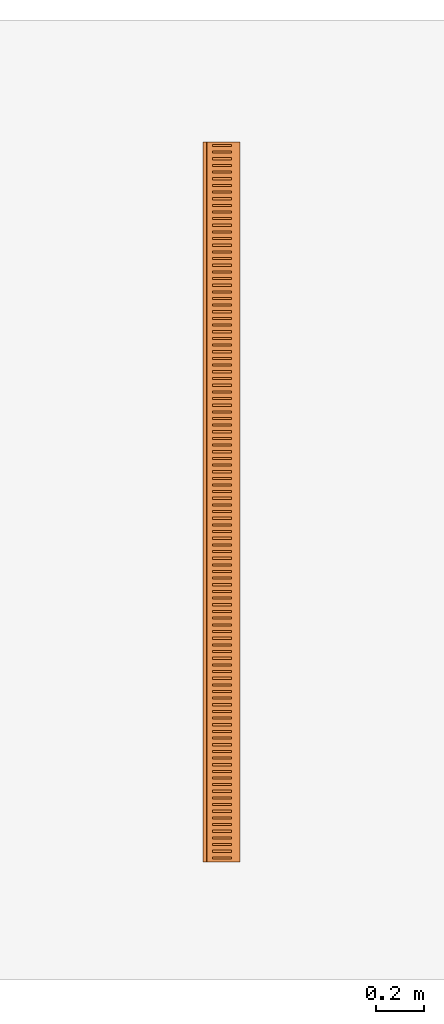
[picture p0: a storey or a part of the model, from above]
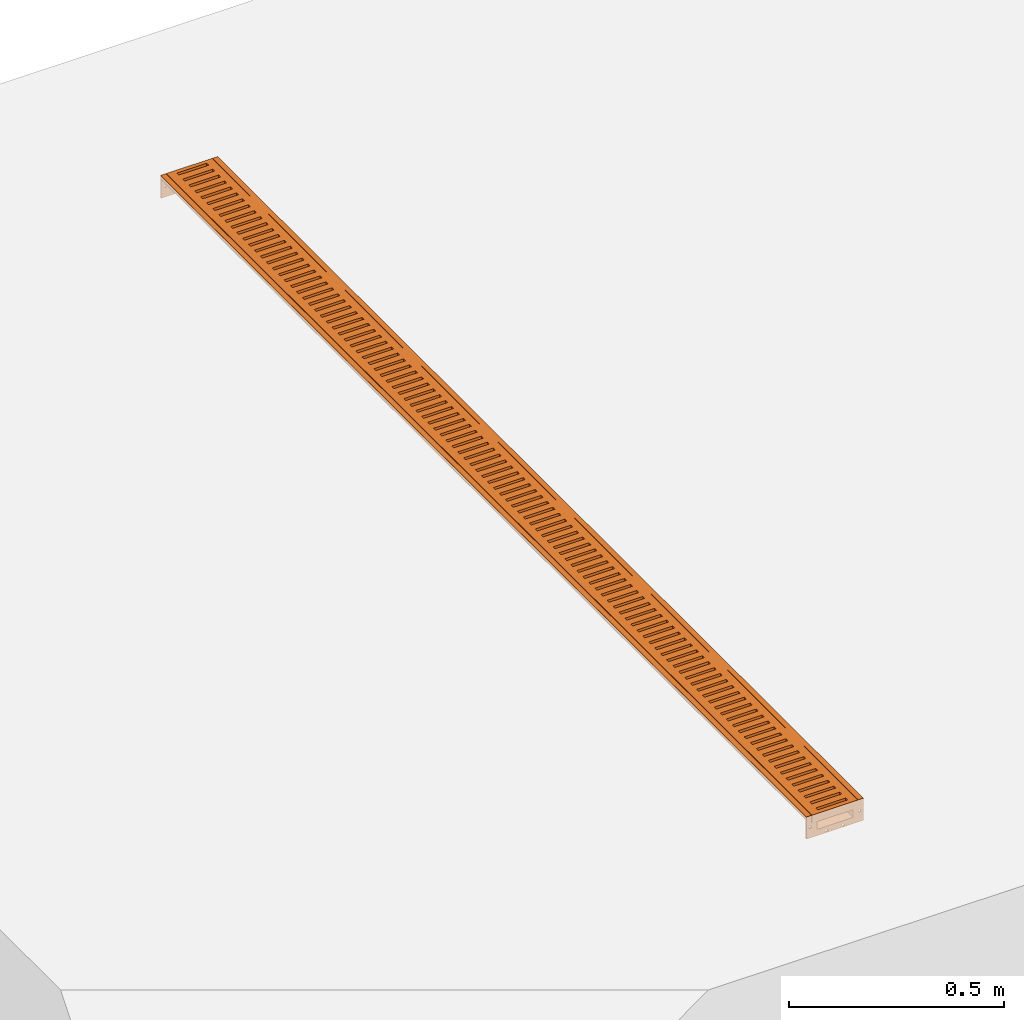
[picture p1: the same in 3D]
Properties of the parts of a building model (IFC2X3)

# File
Description: ViewDefinition [CoordinationView]
File name: 105257 - Level Invert Channel-3000mm LG.ifc
Time: 2014-03-20T14:47:02
Written by: Autodesk Revit 2013
Made in: 20120221_2030(x64)

# IfcProject, Project Number
LongName: Project Name; Phase: Project Status

# IfcSite, Default
RefLatitude: 42, 21, 30, 344238; RefLongitude: -71, -3, -35, -194702; RefElevation: 0 mm

# IfcBuilding
Pset_BuildingCommon - NumberOfStoreys: 1
Other - Project Issue Date: Issue Date; Client Name: Owner; Project Number: Project Number; Project Name: Project Name; Project Status: Project Status; Project Address: ## Street City, State Zip

# IfcBuildingStorey, Level 1
LongName: Level 1; Elevation: 0 mm
Constraints - Elevation Base: 0; Elevation: 0 mm
Graphics - Symbol: M_Level Head - Circle: M_Level Head - Circle; Line Pattern: Center; Color: 0; Symbol at End 1 Default: no; Symbol at End 2 Default: yes; Line Weight: 1
Identity Data - Name: Level 1; Structural: no; Building Story: yes
Dimensions - Computation Height: 0 mm

# IfcBuildingElementProxy: 105257 - Level Invert Channel-3000mm LG, ACO BD Deckline 125 Straight Channel:105257 - Level Invert Channel-3000mm LG:105257 - Level Invert Channel-3000mm LG:225886
In: Level 1
Material: Steel, Galvanized
Construction - 105509 - C250 Perforated Grating - 1000mm Long: no; 15704 - Composite Grating (Black) - 500mm Long: no; 105251 - Endplate - Invert 1: no; 105251 - Endplate - Invert 2: no; 105525 - C250 Slotted Grating - 1000mm Long: no; 105523 - A15 Slotted Grating - 1000mm Long: no; 105508 - C250 Perforated Grating - 500mm Long: no; 10735 - Composite Grating (White) - 500mm Long: no; 105524 - C250 Slotted Grating - 500mm Long: no; 105522 - A15 Slotted Grating - 500mm Long: no; Standard Channel: yes; Grating: yes; Non Standard Channel: no
Phasing - Phase Created: New Construction
Dimensions - Custom Channel: 494 mm; EndCap Distance: 3000 mm; Length: 500 mm; Custom Void: 0 mm; Void Length: -3000 mm; Volume: 8270573 mm3; Channel Len: 2994 mm
Constraints - Moves With Nearby Elements: no; Level: Level: Level 1
Pset_BuildingElementProxyCommon - Reference: 105257 - Level Invert Channel-3000mm LG
Identity Data - Website: www.acobd.com; Watermarked By: www.aco.co.uk; E-mail Technical: abdtechnical@aco.co.uk; Address: ACO Business Centre, Caxton Road, Bedford, MK41 0LF; Watermarked With: BIM Manager Premium Suite; Manufacturer: ACO Building Drainage; Telephone: +44 (0)1462 816666; Watermark1: This file is the property of ACO Technologies PLC; E-mail Sales: abdcommercial@aco.co.uk; Fax: +44 (0)1462 851490; Watermark2: This file is water marked and users are prohibited to reproduce, adapt, distribute this information
General - Product Standard: BS EN 1433:2002 CE marked; Load Class: A15 - C250; Channel Colour: Galvanised; Product Description: ACO Deckline Level Invert Channel (3000 Long); Price: POA - contact ACO; Product Type: shallow invert surface water drainage system; Channel Recyclable: Fully recyclable; Seal Material: Neoprene; Product Code: 105257; Seal Colour: Black; Channel Material: Hot Dipped Galvanised Steel; Product Range: ACO Deckline 125; Channel Recycled Material Content: 25 - 30 %; Weight (Kg): 10.2; Dimensions (LxWxH): 3000 x 153 x 63; Maintenance guidelines: X:\Electronic Literature\Building Drainage Literature\Deckline\Deckline 125.PDF; Seal Recyclable: Fully recyclable; NBS Specification: NBS Section Q10 Kerbs/edgings/channels/paving accessories, Clause 180 Drainage Channel Systems; Installation guidelines: X:\Electronic Literature\Building Drainage Literature\Deckline\Deckline 125.PDF; Seal Recycled Material Content: 0%
Model Properties - Grating Product Code 10735: Load Class C250 - Composite White - 500mm long - 1.2kg; Grating Product Code 15704: Load Class C250 - Composite Black - 500mm long - 1.2kg; Grating Product Code 105509: Load Class C250 - Perforated Galvanised Steel - 500mm long - 2.3kg; Grating Product Code 105508: Load Class C250 - Perforated Galvanised Steel - 1000mm long - 4.8kg; Grating Product Code 105525: Load Class C250 - Slotted Galvanised Steel - 500mm long - 2.3kg; Grating Product Code 105522: Load Class A15 - Slotted Galvanised Steel - 1000mm long - 2.0kg; Grating Product Code 105523: Load Class A15 - Slotted Galvanised Steel - 500mm long - 1.0kg; Grating Product Code 105524: Load Class C250 - Slotted Galvanised Steel - 1000mm long - 4.7kg

# IfcOpeningElement: Opening
In: Level 1
Constraints - Room Bounding: yes; Height Offset From Level: 0 mm; Level: Level: Level 1; Related to Mass: no
Phasing - Phase Created: New Construction
Dimensions - Thickness: 400 mm; Volume: 6371087608 mm3; Perimeter: 16000 mm; Area: 16000000 mm2
Structural - Enable Analytical Model: no; Structural: no
Analytical Properties - Roughness: 1; Heat Transfer Coefficient (U): 2.615; Absorptance: 0.1; Thermal mass: 604440; Thermal Resistance (R): 0.382409
Construction - Default Thickness: 400 mm; Function: 0
Materials and Finishes - Structural Material: Concrete, Broom Finish
Graphics - Coarse Scale Fill Color: 0

# IfcSlab: Floor:Generic Floor - 400mm, Floor:Generic Floor - 400mm:193825
In: Level 1
PredefinedType: FLOOR; Material: Concrete, Broom Finish 400 mm
Constraints - Room Bounding: yes; Height Offset From Level: 0 mm; Level: Level: Level 1; Related to Mass: no
Phasing - Phase Created: New Construction
Dimensions - Thickness: 400 mm; Volume: 6371087608 mm3; Perimeter: 16000 mm; Area: 16000000 mm2
Structural - Enable Analytical Model: no; Structural: no
Pset_SlabCommon - Reference: Generic Floor - 400mm; IsExternal: no; LoadBearing: yes
Analytical Properties - Roughness: 1; Heat Transfer Coefficient (U): 2.615; Absorptance: 0.1; Thermal mass: 604440; Thermal Resistance (R): 0.382409
Construction - Default Thickness: 400 mm; Function: 0
Materials and Finishes - Structural Material: Concrete, Broom Finish
Graphics - Coarse Scale Fill Color: 0
